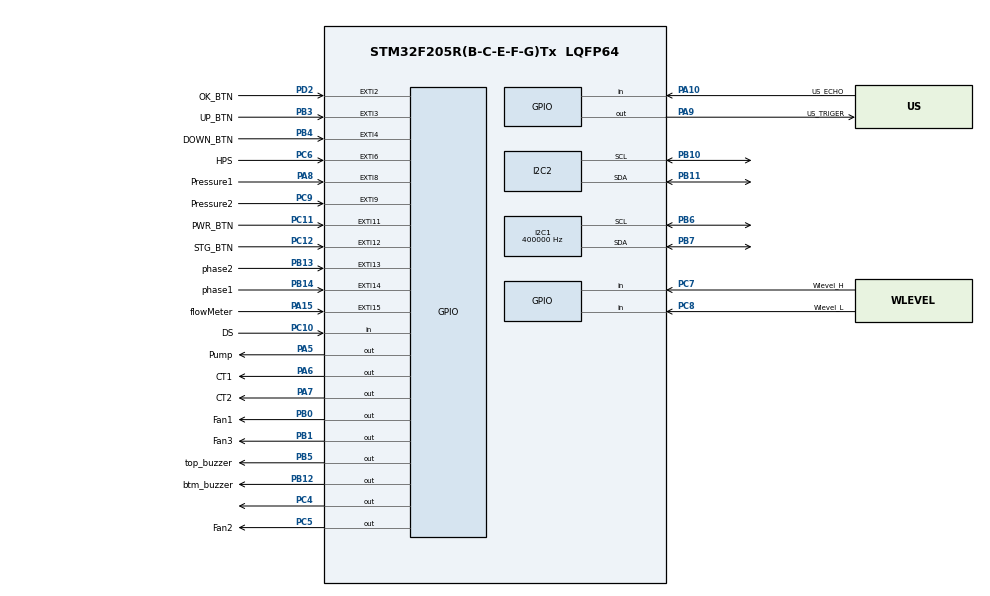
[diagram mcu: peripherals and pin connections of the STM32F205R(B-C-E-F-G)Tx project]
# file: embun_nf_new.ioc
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FREERTOS.Tasks01=bspTask,16,1024,StartDefaultTask,Default,NULL,Dynamic,NULL,NULL;button_task,24,2048,taskButton,As external,NULL,Dynamic,NULL,NULL;taskSensor,8,1024,SensorTask,As external,NULL,Dynamic,NULL,NULL;taskInterface,24,4096,InterfaceTask,As external,NULL,Dynamic,NULL,NULL;systemTask,8,512,taskSystem,As external,NULL,Dynamic,NULL,NULL
FREERTOS.configMAX_CO_ROUTINE_PRIORITIES=4
FREERTOS.configMINIMAL_STACK_SIZE=256
FREERTOS.configTIMER_TASK_PRIORITY=4
FREERTOS.configTOTAL_HEAP_SIZE=40960
FREERTOS.configUSE_NEWLIB_REENTRANT=1
I2C1.ClockSpeed=400000
I2C1.I2C_Mode=I2C_Fast
I2C2.I2C_Mode=I2C_Standard
IWDG.Prescaler=IWDG_PRESCALER_64
Mcu.Family=STM32F2
Mcu.Name=STM32F205R(B-C-E-F-G)Tx
Mcu.Package=LQFP64
NVIC.EXTI15_10_IRQn=true\:5\:0\:false\:false\:true\:true\:true\:true
NVIC.EXTI2_IRQn=true\:5\:0\:false\:false\:true\:true\:true\:true
NVIC.EXTI3_IRQn=true\:5\:0\:false\:false\:true\:true\:true\:true
NVIC.EXTI4_IRQn=true\:5\:0\:false\:false\:true\:true\:true\:true
NVIC.EXTI9_5_IRQn=true\:5\:0\:false\:false\:true\:true\:true\:true
NVIC.I2C1_EV_IRQn=true\:5\:0\:false\:false\:true\:true\:true\:true
NVIC.PriorityGroup=NVIC_PRIORITYGROUP_4
NVIC.TIM1_UP_TIM10_IRQn=true\:15\:0\:false\:false\:true\:false\:false\:true
NVIC.TIM8_TRG_COM_TIM14_IRQn=true\:5\:0\:false\:false\:true\:true\:true\:true
NVIC.TimeBase=TIM1_UP_TIM10_IRQn
NVIC.TimeBaseIP=TIM1
PA10.GPIO_Label=US_ECHO
PA10.GPIO_PuPd=GPIO_PULLUP
PA10.Signal=GPIO_Input
PA15.GPIO_Label=flowMeter
PA15.GPIO_ModeDefaultEXTI=GPIO_MODE_IT_FALLING
PA15.GPIO_PuPd=GPIO_NOPULL
PA15.Signal=GPXTI15
PA5.GPIO_Label=Pump
PA5.GPIO_PuPd=GPIO_PULLUP
PA5.GPIO_Speed=GPIO_SPEED_FREQ_MEDIUM
PA5.PinState=GPIO_PIN_SET
PA5.Signal=GPIO_Output
PA6.GPIO_Label=CT1
PA6.GPIO_PuPd=GPIO_PULLUP
PA6.GPIO_Speed=GPIO_SPEED_FREQ_MEDIUM
PA6.PinState=GPIO_PIN_SET
PA6.Signal=GPIO_Output
PA7.GPIO_Label=CT2
PA7.GPIO_PuPd=GPIO_PULLUP
PA7.GPIO_Speed=GPIO_SPEED_FREQ_MEDIUM
PA7.PinState=GPIO_PIN_SET
PA7.Signal=GPIO_Output
PA8.GPIO_Label=Pressure1
PA8.Signal=GPXTI8
PA9.GPIO_Label=US_TRIGER
PA9.GPIO_Speed=GPIO_SPEED_FREQ_MEDIUM
PA9.PinState=GPIO_PIN_RESET
PA9.Signal=GPIO_Output
PB0.GPIO_Label=Fan1
PB0.GPIO_PuPd=GPIO_PULLUP
PB0.GPIO_Speed=GPIO_SPEED_FREQ_MEDIUM
PB0.PinState=GPIO_PIN_SET
PB0.Signal=GPIO_Output
PB1.GPIO_Label=Fan3
PB1.GPIO_PuPd=GPIO_PULLUP
PB1.GPIO_Speed=GPIO_SPEED_FREQ_MEDIUM
PB1.PinState=GPIO_PIN_SET
PB1.Signal=GPIO_Output
PB10.GPIO_Pu=GPIO_PULLUP
PB10.Mode=I2C
PB10.Signal=I2C2_SCL
PB11.GPIO_Pu=GPIO_PULLUP
PB11.Mode=I2C
PB11.Signal=I2C2_SDA
PB12.GPIO_Label=btm_buzzer
PB12.GPIO_Speed=GPIO_SPEED_FREQ_MEDIUM
PB12.Signal=GPIO_Output
PB13.GPIO_Label=phase2
PB13.GPIO_ModeDefaultEXTI=GPIO_MODE_IT_FALLING
PB13.GPIO_PuPd=GPIO_PULLUP
PB13.Signal=GPXTI13
PB14.GPIO_Label=phase1
PB14.GPIO_ModeDefaultEXTI=GPIO_MODE_IT_FALLING
PB14.GPIO_PuPd=GPIO_PULLUP
PB14.Signal=GPXTI14
PB3.GPIO_Label=UP_BTN
PB3.GPIO_ModeDefaultEXTI=GPIO_MODE_IT_FALLING
PB3.GPIO_PuPd=GPIO_PULLUP
PB3.Signal=GPXTI3
PB4.GPIO_Label=DOWN_BTN
PB4.GPIO_ModeDefaultEXTI=GPIO_MODE_IT_FALLING
PB4.GPIO_PuPd=GPIO_PULLUP
PB4.Signal=GPXTI4
PB5.GPIO_Label=top_buzzer
PB5.GPIO_Speed=GPIO_SPEED_FREQ_MEDIUM
PB5.Signal=GPIO_Output
PB6.GPIO_Pu=GPIO_NOPULL
PB6.Mode=I2C
PB6.Signal=I2C1_SCL
PB7.GPIO_Pu=GPIO_NOPULL
PB7.Mode=I2C
PB7.Signal=I2C1_SDA
PC10.GPIO_Label=DS
PC10.Signal=GPIO_Input
PC11.GPIO_Label=PWR_BTN
PC11.GPIO_ModeDefaultEXTI=GPIO_MODE_IT_FALLING
PC11.GPIO_PuPd=GPIO_PULLUP
PC11.Signal=GPXTI11
PC12.GPIO_Label=STG_BTN
PC12.GPIO_ModeDefaultEXTI=GPIO_MODE_IT_FALLING
PC12.GPIO_PuPd=GPIO_PULLUP
PC12.Signal=GPXTI12
PC14-OSC32_IN.Mode=LSE-External-Oscillator
PC14-OSC32_IN.Signal=RCC_OSC32_IN
PC15-OSC32_OUT.Mode=LSE-External-Oscillator
PC15-OSC32_OUT.Signal=RCC_OSC32_OUT
PC4.GPIO_PuPd=GPIO_PULLUP
PC4.GPIO_Speed=GPIO_SPEED_FREQ_MEDIUM
PC4.PinState=GPIO_PIN_SET
PC4.Signal=GPIO_Output
PC5.GPIO_Label=Fan2
PC5.GPIO_PuPd=GPIO_PULLUP
PC5.GPIO_Speed=GPIO_SPEED_FREQ_MEDIUM
PC5.PinState=GPIO_PIN_SET
PC5.Signal=GPIO_Output
PC6.GPIO_Label=HPS
PC6.Signal=GPXTI6
PC7.GPIO_Label=Wlevel_H
PC7.Signal=GPIO_Input
PC8.GPIO_Label=Wlevel_L
PC8.Signal=GPIO_Input
PC9.GPIO_Label=Pressure2
PC9.Signal=GPXTI9
PD2.GPIO_Label=OK_BTN
PD2.GPIO_ModeDefaultEXTI=GPIO_MODE_IT_FALLING
PD2.GPIO_PuPd=GPIO_PULLUP
PD2.Signal=GPXTI2
PH0-OSC_IN.Mode=HSE-External-Oscillator
PH0-OSC_IN.Signal=RCC_OSC_IN
PH1-OSC_OUT.Mode=HSE-External-Oscillator
PH1-OSC_OUT.Signal=RCC_OSC_OUT
ProjectManager.HeapSize=0x200
ProjectManager.StackSize=0x400
ProjectManager.TargetToolchain=STM32CubeIDE
RCC.48MHZClocksFreq_Value=60000000
RCC.AHBFreq_Value=120000000
RCC.APB1CLKDivider=RCC_HCLK_DIV4
RCC.APB1Freq_Value=30000000
RCC.APB1TimFreq_Value=60000000
RCC.APB2CLKDivider=RCC_HCLK_DIV2
RCC.APB2Freq_Value=60000000
RCC.APB2TimFreq_Value=120000000
RCC.CortexFreq_Value=120000000
RCC.HCLKFreq_Value=120000000
RCC.HSE_VALUE=25000000
RCC.HSI_VALUE=16000000
RCC.PLLM=13
RCC.PLLN=195
RCC.PREFETCH_ENABLE=0
RCC.SYSCLKFreq_VALUE=120000000
RCC.SYSCLKSource=RCC_SYSCLKSOURCE_PLLCLK
RCC.VCOOutputFreq_Value=240000000
RTC.HourFormat=RTC_HOURFORMAT_24
TIM14.AutoReloadPreload=TIM_AUTORELOAD_PRELOAD_ENABLE
TIM14.Period=1000
TIM14.Prescaler=49999
VP_FREERTOS_VS_CMSIS_V2.Mode=CMSIS_V2
VP_IWDG_VS_IWDG.Mode=IWDG_Activate
VP_RTC_VS_RTC_Activate.Mode=RTC_Enabled
VP_RTC_VS_RTC_Calendar.Mode=RTC_Calendar
VP_SYS_VS_tim1.Mode=TIM1
VP_TIM14_VS_ClockSourceINT.Mode=Enable_Timer
board=custom

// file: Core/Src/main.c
/* USER CODE BEGIN Header */
/**
  ******************************************************************************
  * @file           : main.c
  * @brief          : Main program body
  ******************************************************************************
  * @attention
  *
  * Copyright (c) 2022 STMicroelectronics.
  * All rights reserved.
  *
  * This software is licensed under terms that can be found in the LICENSE file
  * in the root directory of this software component.
  * If no LICENSE file comes with this software, it is provided AS-IS.
  *
  ******************************************************************************
  */
/* USER CODE END Header */
#include "main.h"
#include "cmsis_os.h"

/* USER CODE BEGIN Includes */
#include "stdio.h"
#include "string.h"

#include "splashScreen.h"
#include "menuDisplay.h"
#include "stm32_rtc.h"
#include "MCP23017_LCD12864.h"
#include "BSP.h"

#include "eeprom.h"

// task scheduler
#include "sensor.h"
#include "buttonThread.h"
#include "interface.h"
#include "system.h"
/* USER CODE END Includes */

I2C_HandleTypeDef hi2c1;
I2C_HandleTypeDef hi2c2;

IWDG_HandleTypeDef hiwdg;

RTC_HandleTypeDef hrtc;

TIM_HandleTypeDef htim14;

/* Definitions for bspTask */
osThreadId_t bspTaskHandle;
const osThreadAttr_t bspTask_attributes = {
  .name = "bspTask",
  .stack_size = 256 * 4,
  .priority = (osPriority_t) osPriorityBelowNormal,
};
/* Definitions for button_task */
osThreadId_t button_taskHandle;
const osThreadAttr_t button_task_attributes = {
  .name = "button_task",
  .stack_size = 512 * 4,
  .priority = (osPriority_t) osPriorityNormal,
};
/* Definitions for taskSensor */
osThreadId_t taskSensorHandle;
const osThreadAttr_t taskSensor_attributes = {
  .name = "taskSensor",
  .stack_size = 1024 * 4,
  .priority = (osPriority_t) osPriorityLow,
};
/* Definitions for taskInterface */
osThreadId_t taskInterfaceHandle;
const osThreadAttr_t taskInterface_attributes = {
  .name = "taskInterface",
  .stack_size = 1024 * 4,
  .priority = (osPriority_t) osPriorityNormal,
};
/* Definitions for systemTask */
osThreadId_t systemTaskHandle;
const osThreadAttr_t systemTask_attributes = {
  .name = "systemTask",
  .stack_size = 512 * 4,
  .priority = (osPriority_t) osPriorityLow,
};

void SystemClock_Config(void);
static void MX_GPIO_Init(void);
static void MX_RTC_Init(void);
static void MX_I2C1_Init(void);
static void MX_I2C2_Init(void);
static void MX_TIM14_Init(void);
static void MX_IWDG_Init(void);
void StartDefaultTask(void *argument);
extern void taskButton(void *argument);
extern void SensorTask(void *argument);
extern void InterfaceTask(void *argument);
extern void taskSystem(void *argument);

/* USER CODE BEGIN PFP */
uint8_t resetCounter = 0; // for lcd reset

/* USER CODE END PFP */

/* USER CODE BEGIN 0 */
void HAL_GPIO_EXTI_Callback(uint16_t GPIO_Pin)
{
	if(GPIO_Pin == GPIO_PIN_12) // INT Source is pin A9
	{
//		clicked_count++; // Toggle LED
		sensor_phaseCountingUp(0);
	};
	if( GPIO_Pin == phase1_Pin )
		sensor_phaseCountingUp(0);
	if( GPIO_Pin == phase2_Pin )
		sensor_phaseCountingUp(1);
	if( GPIO_Pin == flowMeter_Pin )
		sensor_waterFlowCountingUp();

	// for button interrupt
	switch(GPIO_Pin)
	{
		case PWR_BTN_Pin :
			btnTask.setPressed(BTN_PWR);
			break;
		case STG_BTN_Pin :
			btnTask.setPressed(BTN_SETTING);
			break;
		case OK_BTN_Pin :
			btnTask.setPressed(BTN_OK);
			break;
		case UP_BTN_Pin :
			btnTask.setPressed(BTN_UP);
			break;
		case DOWN_BTN_Pin :
			btnTask.setPressed(BTN_DOWN);
			break;
	}
	system_t.inputInterrupt_handler(GPIO_Pin);
}

void onStandBy(void)
{
	HAL_IWDG_Refresh(&hiwdg);
	char bText[10];
	uint8_t btState=0;
	PORT_IO tmpBtn = {
			.port = PWR_BTN_GPIO_Port,
			.pin = PWR_BTN_Pin,
	};
	button_var tmpBTN;
	button.create(&tmpBTN, tmpBtn, 0, 350UL);
	button.setHoldTime(&tmpBTN, 1500UL);
	lcd.init(&hi2c1, 0x20);
	lcd.clear(1,0);
	lcd.clearBuffer();
	splashScreen.init(splashScreenICO, splashWidth, splashHeight, Font5x7);
	splashScreen.display (CENTER_, "Stand - by", VERSION, 500);
	btState= button.check(&tmpBTN);
	uint32_t count = 0;
	uint8_t flip_ = 1;
	uint32_t timeUp = 0;
	uint8_t blinked=0;
	eeprom_fillBuffer();
	uint8_t eepromRead = 0;
	eepromRead = eeprom_read_buffer(1);
	while( 1 )
	{
		if( HAL_GetTick() - timeUp >= 750 )
		{
			rtc_getDateTime(&date_, &time_);
			blinked =~ blinked;
			timeUp = HAL_GetTick();

//			if( eepromRead >=255 )
//				eepromRead = 0;
//			eepromRead++;
//			eeprom_write_buffer(1, eepromRead);
//			eeprom_flushBuffer();
//			eeprom_fillBuffer();
//			eepromRead = 0;
//			eepromRead = eeprom_read_buffer(1);

		}

		sprintf(bText, "%02d%c%02d%c%02d",  eepromRead/*time_.Hours*/, blinked!=0?':':' ',time_.Minutes, blinked!=0?':':' ', time_.Seconds);
		if( flip_ )
			splashScreen.display(CENTER_, "Stand - by", bText, 75);
		else
			splashScreen.display(CENTER_, " ", bText, 75);
		/*
		lcd.clearBuffer();
			lcd.setFont(Font5x8);
			sprintf(buff,(const char*) " Status : asfafasf ");
			lcd.text(1,15, buff);
			// tank status
			if( true )
			{
				sprintf(buff, " Tank    : filling ");
				lcd.text(1,28, buff);
			}
			else
			{
				sprintf(buff, " Tank    : ");
				lcd.text(1,28, buff);
				lcd.drawBox(41, 28, 54, 8, 1, 1);
				uint8_t fil_ = (uint8_t)(50.f*34/100.f);
				lcd.drawFillBox(43,30,fil_ ,4,1);
				sprintf(buff, (const char*) "45%%");
				uint8_t xpos = 127 - lcd.getWitdthStr((const uint8_t*)buff, strlen(buff));
				lcd.text(xpos,28, buff);
			}

			sprintf(buff, "Currently: 3.5 L");
			lcd.text(1,41, buff);
			sprintf(buff, "Total (M) : 4.6 L/M");
			lcd.text(1,54, buff);
			lcd.sendBuffer(1);
		*/
		btState= button.check(&tmpBTN);
		if( btState == HELD_btn )
			break;
		count++;
		if( count % 2 == 0 )
		{
			count=0;
			flip_ = flip_ > 0 ? 0 : 1;
		}
		HAL_IWDG_Refresh(&hiwdg);
	};
}

/* USER CODE END 0 */

int main(void)
{

  /* MCU Configuration--------------------------------------------------------*/

  /* Reset of all peripherals, Initializes the Flash interface and the Systick. */
  HAL_Init();

  /* Configure the system clock */
  SystemClock_Config();

  /* Initialize all configured peripherals */
  MX_GPIO_Init();
  MX_RTC_Init();
  MX_I2C1_Init();
  MX_I2C2_Init();
  MX_TIM14_Init();
  MX_IWDG_Init();
  /* USER CODE BEGIN 2 */
  system_t.init();
  onStandBy();
//  rtc_getDateTime(&date_, &time_);
//  initEEPROM();

  /* USER CODE END 2 */

  /* Init scheduler */
  osKernelInitialize();

  /* Create the thread(s) */
  /* creation of bspTask */
  bspTaskHandle = osThreadNew(StartDefaultTask, NULL, &bspTask_attributes);

  /* creation of button_task */
  button_taskHandle = osThreadNew(taskButton, NULL, &button_task_attributes);

  /* creation of taskSensor */
  taskSensorHandle = osThreadNew(SensorTask, NULL, &taskSensor_attributes);

  /* creation of taskInterface */
  taskInterfaceHandle = osThreadNew(InterfaceTask, NULL, &taskInterface_attributes);

  /* creation of systemTask */
  systemTaskHandle = osThreadNew(taskSystem, NULL, &systemTask_attributes);

  /* Start scheduler */
  osKernelStart();

  /* We should never get here as control is now taken by the scheduler */
  /* Infinite loop */
  while (1)
  {

  }
}

void SystemClock_Config(void)
{
  RCC_OscInitTypeDef RCC_OscInitStruct = {0};
  RCC_ClkInitTypeDef RCC_ClkInitStruct = {0};
  RCC_PeriphCLKInitTypeDef PeriphClkInitStruct = {0};

  /** Initializes the RCC Oscillators according to the specified parameters
  * in the RCC_OscInitTypeDef structure.
  */
  RCC_OscInitStruct.OscillatorType = RCC_OSCILLATORTYPE_HSI|RCC_OSCILLATORTYPE_LSI;
  RCC_OscInitStruct.HSIState = RCC_HSI_ON;
  RCC_OscInitStruct.HSICalibrationValue = RCC_HSICALIBRATION_DEFAULT;
  RCC_OscInitStruct.LSIState = RCC_LSI_ON;
  RCC_OscInitStruct.PLL.PLLState = RCC_PLL_ON;
  RCC_OscInitStruct.PLL.PLLSource = RCC_PLLSOURCE_HSI;
  RCC_OscInitStruct.PLL.PLLM = 16;
  RCC_OscInitStruct.PLL.PLLN = 200;
  RCC_OscInitStruct.PLL.PLLP = RCC_PLLP_DIV2;
  RCC_OscInitStruct.PLL.PLLQ = 4;
  if (HAL_RCC_OscConfig(&RCC_OscInitStruct) != HAL_OK)
  {
    Error_Handler();
  }
  /** Initializes the CPU, AHB and APB buses clocks
  */
  RCC_ClkInitStruct.ClockType = RCC_CLOCKTYPE_HCLK|RCC_CLOCKTYPE_SYSCLK
                              |RCC_CLOCKTYPE_PCLK1|RCC_CLOCKTYPE_PCLK2;
  RCC_ClkInitStruct.SYSCLKSource = RCC_SYSCLKSOURCE_PLLCLK;
  RCC_ClkInitStruct.AHBCLKDivider = RCC_SYSCLK_DIV1;
  RCC_ClkInitStruct.APB1CLKDivider = RCC_HCLK_DIV4;
  RCC_ClkInitStruct.APB2CLKDivider = RCC_HCLK_DIV2;

  if (HAL_RCC_ClockConfig(&RCC_ClkInitStruct, FLASH_LATENCY_3) != HAL_OK)
  {
    Error_Handler();
  }
  PeriphClkInitStruct.PeriphClockSelection = RCC_PERIPHCLK_RTC;
  PeriphClkInitStruct.RTCClockSelection = RCC_RTCCLKSOURCE_LSI;
  if (HAL_RCCEx_PeriphCLKConfig(&PeriphClkInitStruct) != HAL_OK)
  {
    Error_Handler();
  }
}

static void MX_I2C1_Init(void)
{

  hi2c1.Instance = I2C1;
  hi2c1.Init.ClockSpeed = 400000;
  hi2c1.Init.DutyCycle = I2C_DUTYCYCLE_2;
  hi2c1.Init.OwnAddress1 = 0;
  hi2c1.Init.AddressingMode = I2C_ADDRESSINGMODE_7BIT;
  hi2c1.Init.DualAddressMode = I2C_DUALADDRESS_DISABLE;
  hi2c1.Init.OwnAddress2 = 0;
  hi2c1.Init.GeneralCallMode = I2C_GENERALCALL_DISABLE;
  hi2c1.Init.NoStretchMode = I2C_NOSTRETCH_DISABLE;
  if (HAL_I2C_Init(&hi2c1) != HAL_OK)
  {
    Error_Handler();
  }

}

static void MX_I2C2_Init(void)
{

  hi2c2.Instance = I2C2;
  hi2c2.Init.ClockSpeed = 100000;
  hi2c2.Init.DutyCycle = I2C_DUTYCYCLE_2;
  hi2c2.Init.OwnAddress1 = 0;
  hi2c2.Init.AddressingMode = I2C_ADDRESSINGMODE_7BIT;
  hi2c2.Init.DualAddressMode = I2C_DUALADDRESS_DISABLE;
  hi2c2.Init.OwnAddress2 = 0;
  hi2c2.Init.GeneralCallMode = I2C_GENERALCALL_DISABLE;
  hi2c2.Init.NoStretchMode = I2C_NOSTRETCH_DISABLE;
  if (HAL_I2C_Init(&hi2c2) != HAL_OK)
  {
    Error_Handler();
  }

}

static void MX_IWDG_Init(void)
{

  hiwdg.Instance = IWDG;
  hiwdg.Init.Prescaler = IWDG_PRESCALER_128;
  hiwdg.Init.Reload = 4095;
  if (HAL_IWDG_Init(&hiwdg) != HAL_OK)
  {
    Error_Handler();
  }

}

static void MX_RTC_Init(void)
{

  RTC_TimeTypeDef sTime = {0};
  RTC_DateTypeDef sDate = {0};

  /** Initialize RTC Only
  */
  hrtc.Instance = RTC;
  hrtc.Init.HourFormat = RTC_HOURFORMAT_24;
  hrtc.Init.AsynchPrediv = 127;
  hrtc.Init.SynchPrediv = 255;
  hrtc.Init.OutPut = RTC_OUTPUT_DISABLE;
  hrtc.Init.OutPutPolarity = RTC_OUTPUT_POLARITY_HIGH;
  hrtc.Init.OutPutType = RTC_OUTPUT_TYPE_OPENDRAIN;
  if (HAL_RTC_Init(&hrtc) != HAL_OK)
  {
    Error_Handler();
  }

  /* USER CODE BEGIN Check_RTC_BKUP */
  	if( rtc_init() == true )
  		return;
  	else
  	{
  		sTime.Hours = 0x0;
		sTime.Minutes = 0x0;
		sTime.Seconds = 0x0;
		sTime.DayLightSaving = RTC_DAYLIGHTSAVING_NONE;
		sTime.StoreOperation = RTC_STOREOPERATION_RESET;

		sDate.WeekDay = MFG_DAY;
		sDate.Month	  = MFG_MONTH;
		sDate.Date 	  = MFG_DATE;
		sDate.Year 	  = MFG_YEAR;

		rtc_setDateTime(&sDate, &sTime);
  	}
  	return;

  /* USER CODE END Check_RTC_BKUP */

  /** Initialize RTC and set the Time and Date
  */
  sTime.Hours = 0x0;
  sTime.Minutes = 0x0;
  sTime.Seconds = 0x0;
  sTime.DayLightSaving = RTC_DAYLIGHTSAVING_NONE;
  sTime.StoreOperation = RTC_STOREOPERATION_RESET;
  if (HAL_RTC_SetTime(&hrtc, &sTime, RTC_FORMAT_BCD) != HAL_OK)
  {
    Error_Handler();
  }
  sDate.WeekDay = RTC_WEEKDAY_MONDAY;
  sDate.Month = RTC_MONTH_JANUARY;
  sDate.Date = 0x1;
  sDate.Year = 0x0;

  if (HAL_RTC_SetDate(&hrtc, &sDate, RTC_FORMAT_BCD) != HAL_OK)
  {
    Error_Handler();
  }

}

static void MX_TIM14_Init(void)
{

  htim14.Instance = TIM14;
  htim14.Init.Prescaler = 49999;
  htim14.Init.CounterMode = TIM_COUNTERMODE_UP;
  htim14.Init.Period = 1000;
  htim14.Init.ClockDivision = TIM_CLOCKDIVISION_DIV1;
  htim14.Init.AutoReloadPreload = TIM_AUTORELOAD_PRELOAD_ENABLE;
  if (HAL_TIM_Base_Init(&htim14) != HAL_OK)
  {
    Error_Handler();
  }
  /* USER CODE BEGIN TIM14_Init 2 */
  HAL_TIM_Base_Start_IT(&htim14);
  /* USER CODE END TIM14_Init 2 */

}

static void MX_GPIO_Init(void)
{
  GPIO_InitTypeDef GPIO_InitStruct = {0};

  /* GPIO Ports Clock Enable */
  __HAL_RCC_GPIOC_CLK_ENABLE();
  __HAL_RCC_GPIOH_CLK_ENABLE();
  __HAL_RCC_GPIOA_CLK_ENABLE();
  __HAL_RCC_GPIOB_CLK_ENABLE();
  __HAL_RCC_GPIOD_CLK_ENABLE();

  /*Configure GPIO pin Output Level */
  HAL_GPIO_WritePin(GPIOA, Pump_Pin|CT1_Pin|CT2_Pin, GPIO_PIN_SET);

  /*Configure GPIO pin Output Level */
  HAL_GPIO_WritePin(GPIOC, GPIO_PIN_4|Fan2_Pin, GPIO_PIN_SET);

  /*Configure GPIO pin Output Level */
  HAL_GPIO_WritePin(GPIOB, Fan1_Pin|Fan3_Pin, GPIO_PIN_SET);

  /*Configure GPIO pin Output Level */
  HAL_GPIO_WritePin(GPIOB, btm_buzzer_Pin|top_buzzer_Pin, GPIO_PIN_RESET);

  /*Configure GPIO pin Output Level */
  HAL_GPIO_WritePin(US_TRIGER_GPIO_Port, US_TRIGER_Pin, GPIO_PIN_RESET);

  /*Configure GPIO pins : Pump_Pin CT1_Pin CT2_Pin */
  GPIO_InitStruct.Pin = Pump_Pin|CT1_Pin|CT2_Pin;
  GPIO_InitStruct.Mode = GPIO_MODE_OUTPUT_PP;
  GPIO_InitStruct.Pull = GPIO_PULLUP;
  GPIO_InitStruct.Speed = GPIO_SPEED_FREQ_MEDIUM;
  HAL_GPIO_Init(GPIOA, &GPIO_InitStruct);

  /*Configure GPIO pins : PC4 Fan2_Pin */
  GPIO_InitStruct.Pin = GPIO_PIN_4|Fan2_Pin;
  GPIO_InitStruct.Mode = GPIO_MODE_OUTPUT_PP;
  GPIO_InitStruct.Pull = GPIO_PULLUP;
  GPIO_InitStruct.Speed = GPIO_SPEED_FREQ_MEDIUM;
  HAL_GPIO_Init(GPIOC, &GPIO_InitStruct);

  /*Configure GPIO pins : Fan1_Pin Fan3_Pin */
  GPIO_InitStruct.Pin = Fan1_Pin|Fan3_Pin;
  GPIO_InitStruct.Mode = GPIO_MODE_OUTPUT_PP;
  GPIO_InitStruct.Pull = GPIO_PULLUP;
  GPIO_InitStruct.Speed = GPIO_SPEED_FREQ_MEDIUM;
  HAL_GPIO_Init(GPIOB, &GPIO_InitStruct);

  /*Configure GPIO pins : btm_buzzer_Pin top_buzzer_Pin */
  GPIO_InitStruct.Pin = btm_buzzer_Pin|top_buzzer_Pin;
  GPIO_InitStruct.Mode = GPIO_MODE_OUTPUT_PP;
  GPIO_InitStruct.Pull = GPIO_NOPULL;
  GPIO_InitStruct.Speed = GPIO_SPEED_FREQ_MEDIUM;
  HAL_GPIO_Init(GPIOB, &GPIO_InitStruct);

  /*Configure GPIO pins : phase2_Pin phase1_Pin UP_BTN_Pin DOWN_BTN_Pin */
  GPIO_InitStruct.Pin = phase2_Pin|phase1_Pin|UP_BTN_Pin|DOWN_BTN_Pin;
  GPIO_InitStruct.Mode = GPIO_MODE_IT_FALLING;
  GPIO_InitStruct.Pull = GPIO_PULLUP;
  HAL_GPIO_Init(GPIOB, &GPIO_InitStruct);

  /*Configure GPIO pins : HPS_Pin Pressure2_Pin */
  GPIO_InitStruct.Pin = HPS_Pin|Pressure2_Pin;
  GPIO_InitStruct.Mode = GPIO_MODE_IT_RISING;
  GPIO_InitStruct.Pull = GPIO_NOPULL;
  HAL_GPIO_Init(GPIOC, &GPIO_InitStruct);

  /*Configure GPIO pins : Wlevel_H_Pin Wlevel_L_Pin DS_Pin */
  GPIO_InitStruct.Pin = Wlevel_H_Pin|Wlevel_L_Pin|DS_Pin;
  GPIO_InitStruct.Mode = GPIO_MODE_INPUT;
  GPIO_InitStruct.Pull = GPIO_NOPULL;
  HAL_GPIO_Init(GPIOC, &GPIO_InitStruct);

  /*Configure GPIO pin : Pressure1_Pin */
  GPIO_InitStruct.Pin = Pressure1_Pin;
  GPIO_InitStruct.Mode = GPIO_MODE_IT_RISING;
  GPIO_InitStruct.Pull = GPIO_NOPULL;
  HAL_GPIO_Init(Pressure1_GPIO_Port, &GPIO_InitStruct);

  /*Configure GPIO pin : US_TRIGER_Pin */
  GPIO_InitStruct.Pin = US_TRIGER_Pin;
  GPIO_InitStruct.Mode = GPIO_MODE_OUTPUT_PP;
  GPIO_InitStruct.Pull = GPIO_NOPULL;
  GPIO_InitStruct.Speed = GPIO_SPEED_FREQ_MEDIUM;
  HAL_GPIO_Init(US_TRIGER_GPIO_Port, &GPIO_InitStruct);

  /*Configure GPIO pin : US_ECHO_Pin */
  GPIO_InitStruct.Pin = US_ECHO_Pin;
  GPIO_InitStruct.Mode = GPIO_MODE_INPUT;
  GPIO_InitStruct.Pull = GPIO_PULLUP;
  HAL_GPIO_Init(US_ECHO_GPIO_Port, &GPIO_InitStruct);

  /*Configure GPIO pin : flowMeter_Pin */
  GPIO_InitStruct.Pin = flowMeter_Pin;
  GPIO_InitStruct.Mode = GPIO_MODE_IT_FALLING;
  GPIO_InitStruct.Pull = GPIO_NOPULL;
  HAL_GPIO_Init(flowMeter_GPIO_Port, &GPIO_InitStruct);

  /*Configure GPIO pins : PWR_BTN_Pin STG_BTN_Pin */
  GPIO_InitStruct.Pin = PWR_BTN_Pin|STG_BTN_Pin;
  GPIO_InitStruct.Mode = GPIO_MODE_IT_FALLING;
  GPIO_InitStruct.Pull = GPIO_PULLUP;
  HAL_GPIO_Init(GPIOC, &GPIO_InitStruct);

  /*Configure GPIO pin : OK_BTN_Pin */
  GPIO_InitStruct.Pin = OK_BTN_Pin;
  GPIO_InitStruct.Mode = GPIO_MODE_IT_FALLING;
  GPIO_InitStruct.Pull = GPIO_PULLUP;
  HAL_GPIO_Init(OK_BTN_GPIO_Port, &GPIO_InitStruct);

  /* EXTI interrupt init*/
  HAL_NVIC_SetPriority(EXTI2_IRQn, 5, 0);
  HAL_NVIC_EnableIRQ(EXTI2_IRQn);

  HAL_NVIC_SetPriority(EXTI3_IRQn, 5, 0);
  HAL_NVIC_EnableIRQ(EXTI3_IRQn);

  HAL_NVIC_SetPriority(EXTI4_IRQn, 5, 0);
  HAL_NVIC_EnableIRQ(EXTI4_IRQn);

  HAL_NVIC_SetPriority(EXTI9_5_IRQn, 5, 0);
  HAL_NVIC_EnableIRQ(EXTI9_5_IRQn);

  HAL_NVIC_SetPriority(EXTI15_10_IRQn, 5, 0);
  HAL_NVIC_EnableIRQ(EXTI15_10_IRQn);

}

void StartDefaultTask(void *argument)
{
  /* USER CODE BEGIN 5 */
  /* Infinite loop */
//	 initMenu();

//	 float totalVolume = 100;
//	 float tankLevelPercent = 0;
//	 uint8_t tankMode_ = 0;
//	 uint8_t systemStatus_ = 0;
//	 float minTemperature = 25;
//	 float minHumidity = 30;

	   	interfaceMain.attachTimeDate(&date_, &time_);
	 	interfaceMain.attachMeasurement(&sensorVar.air_temperature, &sensorVar.air_rH,
	 								    &sensorVar.fin_temperature[0], &sensorVar.fin_temperature[1],
	 								    &sensorVar.waterFlow_inLPM, &sysVar.memory.totalWaterVolume ,&sysVar.memory.lastWaterVolume, &sensorVar.tankLevel_inPercent,
										&sensorVar.waterLevelFrom_cap);
	 	interfaceMain.attachSystemFlag	(&sysVar.memory.tankMode, &sysVar.sysFlag.tank, &sysVar.sysFlag.systemRun );
	 	interfaceMain.attachSystemSet(&sysVar.memory.minFinTemperature, &sysVar.memory.minHumidity);
	 HAL_IWDG_Refresh(&hiwdg);
	 interfaceMain.init();
	 sensor.sensorStart();
	 while(interfaceMain.isReady() == 0 ) {osDelay(50);};
	 btnTask.begin();
	 uint8_t co = 0;
	 bool flipFlop = false;
  for(;;)
  {
	  co++;
	  if( co% 10 == 0 )
	  {
		  HAL_IWDG_Refresh(&hiwdg);
		  flipFlop = !flipFlop;
		  rtc_getDateTime(&date_, &time_);
		  co = 1;
	  }

	  HAL_IWDG_Refresh(&hiwdg);
//	  tankLevelPercent+=0.1;
//	  totalVolume+=0.5;

	  osDelay(100);
  }
  /* USER CODE END 5 */
}

void HAL_TIM_PeriodElapsedCallback(TIM_HandleTypeDef *htim)
{
  /* USER CODE BEGIN Callback 0 */
	if( htim->Instance==TIM14)
	{
		sensor_phaseUpdateFrequency(0);
		sensor_phaseUpdateFrequency(1);
		sensor_waterFlowUpdateFrequency();
		resetCounter++;
		if( resetCounter >= 10 )
		{

//			lcd.init(&hi2c1, 0x20);
//			interfaceMain.showNotification("POWER SOURCE\n\n is Failed !\n\nPlease Check it ! ", ico_failed, 3000);
			resetCounter = 0;
		}
//		HAL_IWDG_Refresh(&hiwdg);
	}
  /* USER CODE END Callback 0 */
  if (htim->Instance == TIM1) {
    HAL_IncTick();
  }
}

void Error_Handler(void)
{
  /* USER CODE BEGIN Error_Handler_Debug */
  /* User can add his own implementation to report the HAL error return state */
  __disable_irq();
  while (1)
  {
	  system_t.beeper(10000, 1);
  }
  /* USER CODE END Error_Handler_Debug */
}
